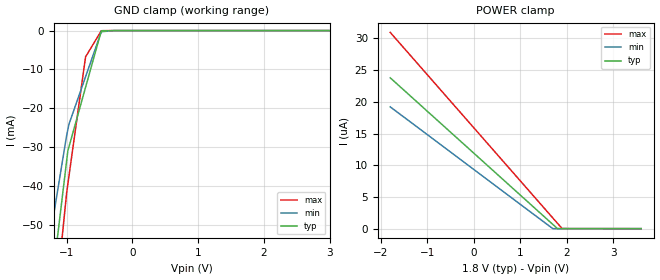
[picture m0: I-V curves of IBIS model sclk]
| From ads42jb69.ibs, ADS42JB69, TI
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|   sclk Model
[Model]   sclk
Model_type   Input
Vinl = 0.4
Vinh = 1.2
|   typ   min   max
|   (nom PVT)   (fast PVT)   (slow PVT)
C_comp   1.286e-12   1.247e-12   1.328e-12
| Where nom  PVT is Nominal Process, 1.8V, 25C
|   Fast PVT is Strong Process,  1.9V, -40C
|   Slow PVT is Weak Process,   1.7V, 125C
[Voltage Range]   1.8   1.7   1.9
|Junction Temperature
[Temperature Range]   25   125   -40
[Power Clamp Reference]   1.8   1.7   1.9
[GND Clamp Reference]   0   0   0
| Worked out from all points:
|   GND clamp passes 1 mA (typ) near -0.49 V on its own axis
[GND Clamp]
|   Voltage   I(typ)   I(min)   I(max)
-1.8V     -820.9mA   -109.7mA   -1.727A
-1.49V    -102.4mA   -77.57mA   -123.3mA
-1.001V   -33.56mA   -27.01mA   -41.82mA
-982.8mV  -30.95mA   -25.49mA   -39.52mA
-965.6mV  -29.91mA   -24.08mA   -37.44mA
-712.5mV  -14.57mA   -11.86mA   -6.761mA
-473.1mV  -76.28uA   -301.7uA   -31.29uA
-278.8mV  -2.295uA   -5.018uA   -2.362uA
3.6V      0A         0A         0A
[POWER Clamp]
|   Voltage   I(typ)   I(min)   I(max)
-1.8V     23.78uA    19.2uA     30.94uA
1.698V    671.7nA    0A         1.687uA
1.798V    11.89nA    0A         851.2nA
1.898V    0A         0A         15.89nA
3.6V      0A         0A         0A
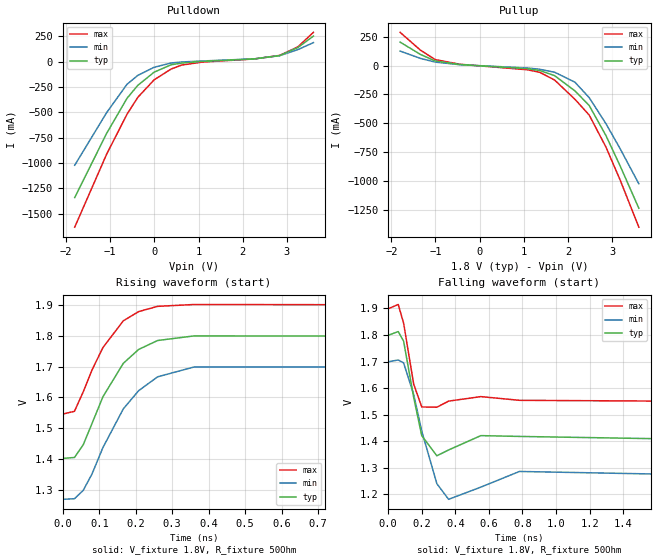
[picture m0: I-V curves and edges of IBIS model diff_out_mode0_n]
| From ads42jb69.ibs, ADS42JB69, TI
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[Model]   diff_out_mode0_n
Model_type   Output
Polarity   Non-Inverting
Vmeas = 1.611
Vref = 1.8
Cref = 0.5pF
Rref = 50
|   typ   min   max
|   (nom PVT)   (fast PVT)   (slow PVT)
C_comp   2.771e-12   2.341e-12   2.803e-12
[Model spec]
|subparameter   typ   min   max
Vmeas   1.611   1.505   1.7254
| Where nom  PVT is Nominal Process, 1.8V, 25C
|   Fast PVT is Strong Process,  1.9V, -40C
|   Slow PVT is Weak Process,   1.7V, 125C
[Voltage Range]   1.8   1.7   1.9
|Junction Temperature
[Temperature Range]   25   125   -40
[Pullup Reference]   1.8   1.7   1.9
[Pulldown Reference]   0   0   0
[Power Clamp Reference]   1.8   1.7   1.9
[GND Clamp Reference]   0   0   0
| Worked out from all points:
|   slope of the pulldown table from 0 to 0.27 V, typ, clamps not added: 5.02 ohm
|   slope of the pullup table from 0 to 0.27 V, typ, clamps not added: 49.4 ohm
|   falling waveform, V_fixture 1.8V, R_fixture 50Ohm: 20-80 % time 63.6ps typ, 89.7ps min, 54.2ps max; typ from 1.8 V to 1.4 V
|   rising waveform, V_fixture 1.8V, R_fixture 50Ohm: 20-80 % time 103ps typ, 118ps min, 92.7ps max; typ from 1.4 V to 1.8 V
[Pulldown]
|   Voltage   I(typ)   I(min)   I(max)
-1.8V     -1.34A     -1.022A    -1.632A
-1.078V   -708.2mA   -503.6mA   -912.9mA
-617.4mV  -362.5mA   -224.1mA   -519.7mA
-373.1mV  -234.5mA   -136.6mA   -352.8mA
-2.6mV    -104.5mA   -56.41mA   -179.8mA
381.6mV   -31.66mA   -14.11mA   -73.7mA
621mV     -15.45mA   -4.391mA   -34.61mA
1.082V    1.461mA    5.463mA    -5.442mA
2.252V    25.55mA    26.17mA    25.09mA
2.836V    58.76mA    57.27mA    60.53mA
3.247V    137.8mA    117.4mA    144.6mA
3.6V      250.8mA    186.5mA    287.9mA
[Pullup]
|   Voltage   I(typ)   I(min)   I(max)
-1.8V     203.7mA    126.2mA    288.4mA
-1.342V   97.45mA    62.7mA     134.5mA
-1.004V   40.03mA    30.51mA    51.97mA
-450mV    9.478mA    7.89mA     12.08mA
1.082V    -26.41mA   -20.41mA   -36.04mA
1.357V    -42.28mA   -31.39mA   -57.53mA
1.695V    -86.58mA   -57.19mA   -124.8mA
2.154V    -218.3mA   -143.2mA   -291.1mA
2.477V    -345.3mA   -277mA     -427.9mA
2.853V    -603.1mA   -500.6mA   -702.9mA
3.176V    -867.5mA   -718.8mA   -989.4mA
3.6V      -1.235A    -1.023A    -1.399A
[Ramp]
R_load = 50
|   typ   min   max
dV/dt_r   0.104408/5.88716e-11   0.137549/7.39915e-11  0.0846468/4.82458e-11
dV/dt_f   0.237884/6.34118e-11   0.258234/8.94292e-11   0.210173/5.41466e-11
[Falling Waveform]
V_fixture = 1.8V
V_fixture_min = 1.7V
V_fixture_max = 1.9V
R_fixture = 50Ohm
|   Time   V(typ)   V(min)   V(max)
0s        1.799V     1.699V     1.899V
60ps      1.813V     1.706V     1.915V
92ps      1.777V     1.695V     1.845V
152ps     1.565V     1.576V     1.615V
200ps     1.421V     1.438V     1.529V
290ps     1.345V     1.24V      1.528V
360ps     1.367V     1.181V     1.551V
552ps     1.421V     1.227V     1.568V
782ps     1.418V     1.286V     1.554V
2.198ns   1.403V     1.269V     1.549V
[Rising Waveform]
V_fixture = 1.8V
V_fixture_min = 1.7V
V_fixture_max = 1.9V
R_fixture = 50Ohm
|   Time   V(typ)   V(min)   V(max)
0s        1.402V     1.269V     1.546V
32ps      1.405V     1.271V     1.555V
56ps      1.446V     1.298V     1.618V
80ps      1.515V     1.351V     1.689V
110ps     1.602V     1.437V     1.762V
166ps     1.711V     1.563V     1.849V
208ps     1.756V     1.622V     1.879V
260ps     1.785V     1.667V     1.896V
360ps     1.8V       1.699V     1.902V
2.168ns   1.798V     1.698V     1.899V
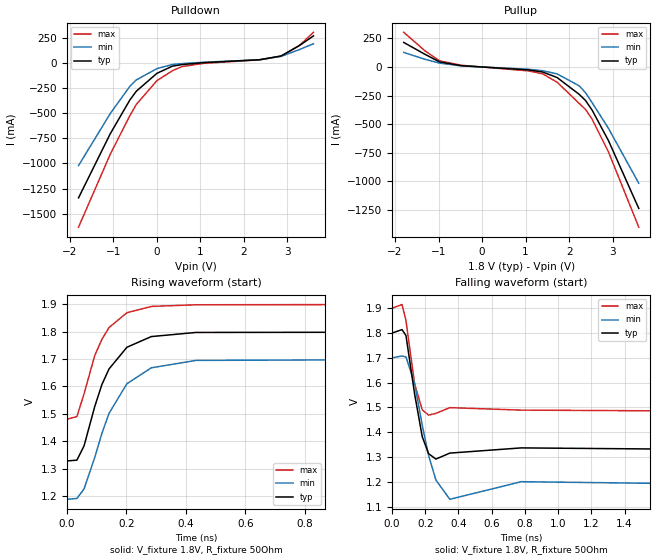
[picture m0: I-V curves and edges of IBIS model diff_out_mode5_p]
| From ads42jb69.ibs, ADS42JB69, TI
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|   diff_out_mode5 Model
[Model]   diff_out_mode5_p
Model_type   Output
Polarity   Non-Inverting
Vmeas = 1.577
Vref = 1.8
Cref = 0.5pF
Rref = 50
|   typ   min   max
|   (nom PVT)   (fast PVT)   (slow PVT)
C_comp   2.997e-12   2.361e-12   3.042e-12
[Model spec]
|subparameter   typ   min   max
Vmeas   1.577   1.48   1.695
| Where nom  PVT is Nominal Process, 1.8V, 25C
|   Fast PVT is Strong Process,  1.9V, -40C
|   Slow PVT is Weak Process,   1.7V, 125C
[Voltage Range]   1.8   1.7   1.9
[Temperature Range]   25   125   -40
[Pullup Reference]   1.8   1.7   1.9
[Pulldown Reference]   0   0   0
[Power Clamp Reference]   1.8   1.7   1.9
[GND Clamp Reference]   0   0   0
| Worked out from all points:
|   slope of the pulldown table from 0 to 0.27 V, typ, clamps not added: 5.01 ohm
|   slope of the pullup table from 0 to 0.27 V, typ, clamps not added: 49.4 ohm
|   falling waveform, V_fixture 1.8V, R_fixture 50Ohm: 20-80 % time 62ps typ, 90.4ps min, 54.3ps max; typ from 1.8 V to 1.33 V
|   rising waveform, V_fixture 1.8V, R_fixture 50Ohm: 20-80 % time 97.2ps typ, 111ps min, 86.4ps max; typ from 1.33 V to 1.8 V
[Pulldown]
|   Voltage   I(typ)   I(min)   I(max)
-1.8V     -1.342A    -1.021A    -1.634A
-1.068V   -701.7mA   -500.4mA   -905.2mA
-621mV    -368.2mA   -232.2mA   -524.5mA
-473.1mV  -280.6mA   -168.1mA   -412mA
11.97fV   -102.4mA   -55.57mA   -176mA
356.4mV   -30.74mA   -13.97mA   -76.24mA
577.6mV   -15.02mA   -4.751mA   -35.16mA
1.066V    4.027mA    8.146mA    -3.07mA
2.362V    33.35mA    33.41mA    32.61mA
2.856V    71.04mA    67.02mA    68.88mA
3.276V    174.8mA    134.4mA    175.2mA
3.6V      270.8mA    192.5mA    306.4mA
[Pullup]
|   Voltage   I(typ)   I(min)   I(max)
-1.8V     213.7mA    126.4mA    302.2mA
-1.311V   109.8mA    66.53mA    140.1mA
-976.6mV  43.33mA    33.15mA    53.42mA
-473.1mV  10.75mA    8.557mA    14.04mA
1.064V    -26.2mA    -20.32mA   -34.77mA
1.389V    -44.27mA   -32.84mA   -60.2mA
1.723V    -92.6mA    -60.64mA   -133.1mA
2.234V    -240.5mA   -165.9mA   -319.8mA
2.379V    -294.3mA   -226.3mA   -372.8mA
2.529V    -378mA     -312.4mA   -457.3mA
2.903V    -643mA     -535.9mA   -741.2mA
3.6V      -1.236A    -1.016A    -1.4A
[Ramp]
R_load = 50
|   typ   min   max
dV/dt_r   0.116059/4.68643e-11   0.152052/6.08909e-11   0.0942144/3.82695e-11
dV/dt_f   0.282398/6.19918e-11   0.306207/9.04217e-11   0.249232/5.37832e-11
[Falling Waveform]
V_fixture = 1.8V
V_fixture_min = 1.7V
V_fixture_max = 1.9V
R_fixture = 50Ohm
|   Time   V(typ)   V(min)   V(max)
0s        1.799V     1.699V     1.899V
60ps      1.813V     1.707V     1.914V
84ps      1.789V     1.703V     1.849V
136ps     1.554V     1.596V     1.595V
182ps     1.382V     1.428V     1.49V
220ps     1.314V     1.307V     1.469V
264ps     1.292V     1.208V     1.476V
348ps     1.316V     1.13V      1.499V
778ps     1.337V     1.201V     1.489V
2.208ns   1.329V     1.189V     1.484V
[Rising Waveform]
V_fixture = 1.8V
V_fixture_min = 1.7V
V_fixture_max = 1.9V
R_fixture = 50Ohm
|   Time   V(typ)   V(min)   V(max)
0s        1.328V     1.188V     1.48V
34ps      1.331V     1.191V     1.49V
58ps      1.383V     1.226V     1.573V
94ps      1.527V     1.341V     1.713V
118ps     1.607V     1.429V     1.772V
142ps     1.664V     1.502V     1.815V
202ps     1.743V     1.61V      1.869V
284ps     1.782V     1.668V     1.892V
434ps     1.797V     1.695V     1.898V
1.198ns   1.798V     1.698V     1.899V
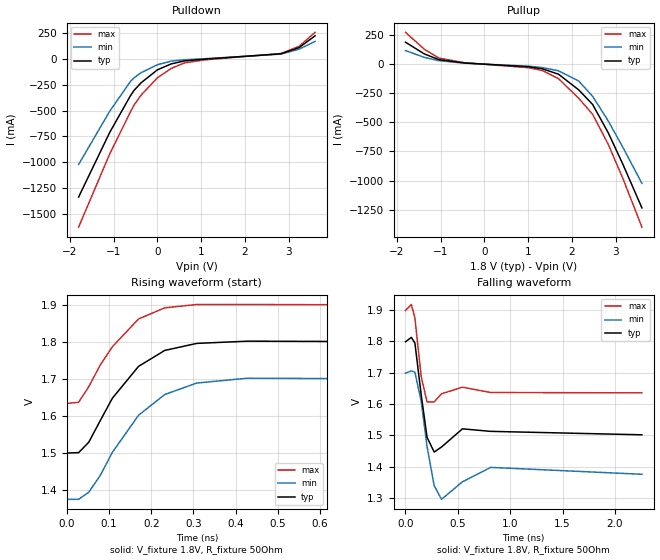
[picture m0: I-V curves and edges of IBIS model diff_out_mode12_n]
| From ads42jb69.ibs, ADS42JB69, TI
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[Model]   diff_out_mode12_n
Model_type   Output
Polarity   Non-Inverting
Vmeas = 1.659
Vref = 1.8
Cref = 0.5pF
Rref = 50
|   typ   min   max
|   (nom PVT)   (fast PVT)   (slow PVT)
C_comp   2.611e-12   2.311e-12   2.731e-12
[Model Spec]
Vmeas   1.659   1.56   1.757
| Where nom  PVT is Nominal Process, 1.8V, 25C
|   Fast PVT is Strong Process,  1.9V, -40C
|   Slow PVT is Weak Process,   1.7V, 120C
[Voltage Range]   1.8   1.7   1.9
[Temperature Range]   25   120   -40
[Pullup Reference]   1.8   1.7   1.9
[Pulldown Reference]   0   0   0
[Power Clamp Reference]   1.8   1.7   1.9
[GND Clamp Reference]   0   0   0
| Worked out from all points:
|   slope of the pulldown table from 0 to 0.27 V, typ, clamps not added: 5.18 ohm
|   slope of the pullup table from 0 to 0.27 V, typ, clamps not added: 49.4 ohm
|   falling waveform, V_fixture 1.8V, R_fixture 50Ohm: 20-80 % time 57.2ps typ, 77.2ps min, 49.6ps max; typ from 1.8 V to 1.5 V
|   rising waveform, V_fixture 1.8V, R_fixture 50Ohm: 20-80 % time 107ps typ, 120ps min, 97ps max; typ from 1.5 V to 1.8 V
[Pulldown]
|   Voltage   I(typ)   I(min)   I(max)
-1.8V     -1.336A    -1.021A    -1.627A
-1.089V   -710.8mA   -506.3mA   -918.4mA
-618.5mV  -358.3mA   -219.8mA   -514.9mA
-536.4mV  -306.2mA   -183.8mA   -448.2mA
-373.1mV  -231.6mA   -133.7mA   -350.4mA
-1.8mV    -106.4mA   -57.01mA   -183.2mA
316.5mV   -48.43mA   -21.37mA   -91.53mA
621mV     -19.52mA   -8.364mA   -38.77mA
1.082V    -2.543mA   1.491mA    -9.459mA
2.819V    48.74mA    46.01mA    51.78mA
3.237V    109.3mA    94.39mA    121.5mA
3.6V      222.8mA    168.4mA    256.6mA
[Pullup]
|   Voltage   I(typ)   I(min)   I(max)
-1.8V     187.8mA    116mA      272.7mA
-1.368V   87.07mA    57.51mA    126.7mA
-1.034V   37.99mA    28.94mA    51.33mA
-450mV    9.292mA    7.813mA    11.7mA
1.005V    -22.9mA    -18.07mA   -31.06mA
1.325V    -40.4mA    -30.03mA   -54.96mA
1.694V    -86.71mA   -57.49mA   -124.8mA
2.154V    -220.6mA   -144.8mA   -292.8mA
2.474V    -346.5mA   -276.7mA   -430.6mA
2.831V    -590.1mA   -488.5mA   -689.3mA
3.168V    -862.6mA   -716.5mA   -984.7mA
3.6V      -1.235A    -1.024A    -1.4A
[Ramp]
R_load = 50
|   typ   min   max
dV/dt_r   0.0865637/6.18375e-11   0.113039/7.77451e-11  0.0700683/5.3822e-11
dV/dt_f   0.178438/5.71779e-11   0.193852/7.66122e-11   0.157878/4.94553e-11
[Falling Waveform]
V_fixture = 1.8V
V_fixture_min = 1.7V
V_fixture_max = 1.9V
R_fixture = 50Ohm
|   Time   V(typ)   V(min)   V(max)
0s        1.799V     1.699V     1.899V
56ps      1.813V     1.706V     1.918V
90ps      1.795V     1.702V     1.875V
150ps     1.63V      1.609V     1.688V
206ps     1.494V     1.464V     1.607V
274ps     1.447V     1.34V      1.607V
344ps     1.463V     1.296V     1.633V
544ps     1.521V     1.352V     1.654V
814ps     1.513V     1.398V     1.637V
2.258ns   1.502V     1.376V     1.636V
[Rising Waveform]
V_fixture = 1.8V
V_fixture_min = 1.7V
V_fixture_max = 1.9V
R_fixture = 50Ohm
|   Time   V(typ)   V(min)   V(max)
0s        1.501V     1.376V     1.635V
28ps      1.502V     1.376V     1.638V
52ps      1.53V      1.395V     1.68V
80ps      1.59V      1.442V     1.74V
108ps     1.649V     1.503V     1.788V
170ps     1.735V     1.603V     1.863V
232ps     1.778V     1.659V     1.893V
308ps     1.797V     1.69V      1.902V
428ps     1.803V     1.703V     1.902V
1.414ns   1.799V     1.698V     1.899V
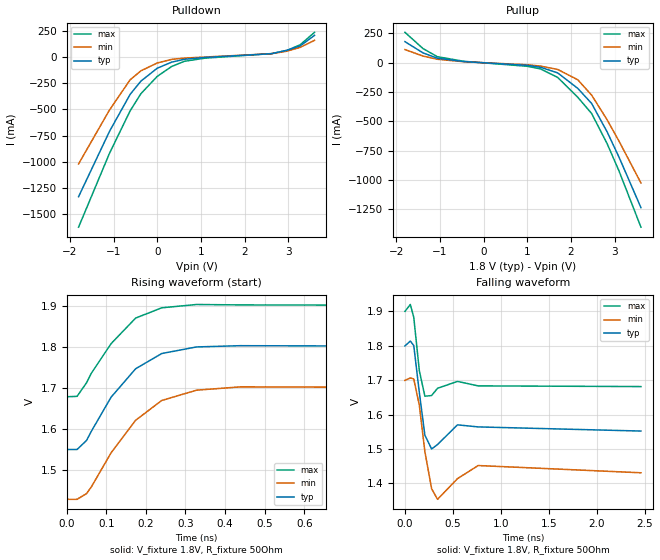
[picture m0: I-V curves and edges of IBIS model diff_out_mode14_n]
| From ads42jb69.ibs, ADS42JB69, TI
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[Model]   diff_out_mode14_n
Model_type   Output
Polarity   Non-Inverting
Vmeas = 1.683
Vref = 1.8
Cref = 0.5pF
Rref = 50
|   typ   min   max
|   (nom PVT)   (fast PVT)   (slow PVT)
C_comp   2.559e-12   2.312e-12   2.683e-12
[Model spec]
|subparameter   typ   min   max
Vmeas   1.683   1.583   1.783
| Where nom  PVT is Nominal Process, 1.8V, 25C
|   Fast PVT is Strong Process,  1.9V, -40C
|   Slow PVT is Weak Process,   1.7V, 125C
[Voltage Range]   1.8   1.7   1.9
|Junction Temperature
[Temperature Range]   25   125   -40
[Pullup Reference]   1.8   1.7   1.9
[Pulldown Reference]   0   0   0
[Power Clamp Reference]   1.8   1.7   1.9
[GND Clamp Reference]   0   0   0
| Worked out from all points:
|   slope of the pulldown table from 0 to 0.27 V, typ, clamps not added: 5.26 ohm
|   slope of the pullup table from 0 to 0.27 V, typ, clamps not added: 49.4 ohm
|   falling waveform, V_fixture 1.8V, R_fixture 50Ohm: 20-80 % time 54.8ps typ, 71.4ps min, 48.3ps max; typ from 1.8 V to 1.55 V
|   rising waveform, V_fixture 1.8V, R_fixture 50Ohm: 20-80 % time 111ps typ, 123ps min, 100ps max; typ from 1.55 V to 1.8 V
[Pulldown]
|   Voltage   I(typ)   I(min)   I(max)
-1.8V     -1.334A    -1.021A    -1.625A
-1.093V   -710.6mA   -506.3mA   -920.2mA
-621mV    -357.1mA   -218mA     -514.7mA
-373.1mV  -230mA     -131.9mA   -350mA
-700uV    -107.2mA   -57.2mA    -185.2mA
329.9mV   -49.06mA   -22.56mA   -90.4mA
621mV     -21.57mA   -10.36mA   -40.99mA
1.088V    -4.429mA   -403.7uA   -11.25mA
2.612V    31.31mA    31.35mA    32.68mA
2.965V    64.16mA    55.57mA    61.83mA
3.271V    106mA      91.87mA    117.4mA
3.6V      206.9mA    159.7mA    235.7mA
[Pullup]
|   Voltage   I(typ)   I(min)   I(max)
-1.8V     179.1mA    111.6mA    258.5mA
-1.386V   83.23mA    56.24mA    119.9mA
-1.059V   37.91mA    29.09mA    51.01mA
-450mV    9.277mA    7.808mA    11.61mA
1.005V    -22.92mA   -18.08mA   -31.09mA
1.3V      -38.86mA   -28.94mA   -53.02mA
1.694V    -86.94mA   -57.68mA   -125.1mA
2.154V    -218.8mA   -145.5mA   -294.3mA
2.472V    -347.5mA   -276.5mA   -433.1mA
2.826V    -589.3mA   -486.6mA   -689.7mA
3.098V    -804.6mA   -668.2mA   -922.3mA
3.6V      -1.235A    -1.025A    -1.401A
[Ramp]
R_load = 50
|   typ   min   max
dV/dt_r   0.0762883/6.61619e-11  0.0996219/8.30193e-11  0.0616713/5.96022e-11
dV/dt_f   0.148859/5.50326e-11   0.161586/7.12222e-11   0.132027/4.81177e-11
[Falling Waveform]
V_fixture = 1.8V
V_fixture_min = 1.7V
V_fixture_max = 1.9V
R_fixture = 50Ohm
|   Time   V(typ)   V(min)   V(max)
0s        1.799V     1.699V     1.899V
56ps      1.813V     1.706V     1.919V
92ps      1.8V       1.703V     1.882V
150ps     1.664V     1.627V     1.727V
208ps     1.54V      1.492V     1.653V
278ps     1.5V       1.385V     1.655V
340ps     1.513V     1.354V     1.676V
548ps     1.57V      1.414V     1.696V
764ps     1.564V     1.452V     1.683V
2.462ns   1.552V     1.431V     1.681V
[Rising Waveform]
V_fixture = 1.8V
V_fixture_min = 1.7V
V_fixture_max = 1.9V
R_fixture = 50Ohm
|   Time   V(typ)   V(min)   V(max)
0s        1.551V     1.43V      1.679V
26ps      1.551V     1.43V      1.68V
50ps      1.573V     1.444V     1.713V
62ps      1.595V     1.46V      1.736V
112ps     1.678V     1.543V     1.808V
174ps     1.747V     1.622V     1.87V
240ps     1.784V     1.67V      1.895V
328ps     1.8V       1.695V     1.903V
438ps     1.803V     1.703V     1.902V
2ns       1.799V     1.699V     1.899V
